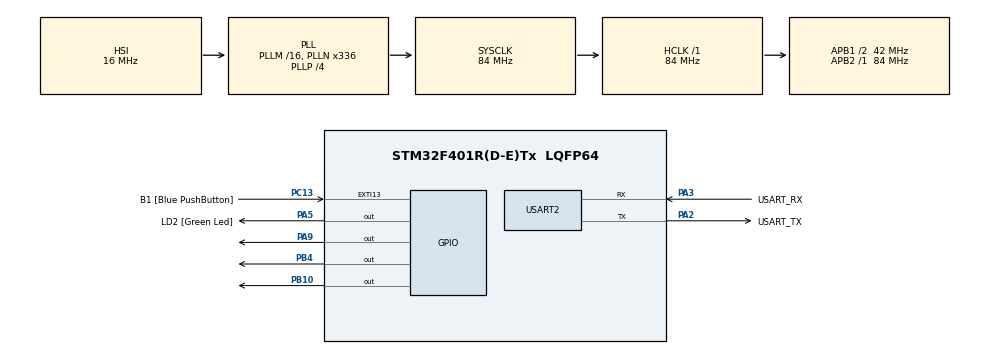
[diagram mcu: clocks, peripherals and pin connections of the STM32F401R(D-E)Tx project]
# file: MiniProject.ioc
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Mcu.Family=STM32F4
Mcu.Name=STM32F401R(D-E)Tx
Mcu.Package=LQFP64
NVIC.PriorityGroup=NVIC_PRIORITYGROUP_4
NVIC.TIM1_BRK_TIM9_IRQn=true\:0\:0\:false\:false\:true\:false\:true\:true
NVIC.TimeBase=TIM1_BRK_TIM9_IRQn
NVIC.TimeBaseIP=TIM9
NVIC.USART2_IRQn=true\:6\:0\:true\:false\:true\:true\:true\:true
PA13.GPIO_Label=TMS
PA13.Signal=SYS_JTMS-SWDIO
PA14.GPIO_Label=TCK
PA14.Signal=SYS_JTCK-SWCLK
PA2.GPIO_Label=USART_TX
PA2.GPIO_Mode=GPIO_MODE_AF_PP
PA2.GPIO_PuPd=GPIO_NOPULL
PA2.GPIO_Speed=GPIO_SPEED_FREQ_LOW
PA2.Mode=Asynchronous
PA2.Signal=USART2_TX
PA3.GPIO_Label=USART_RX
PA3.GPIO_Mode=GPIO_MODE_AF_PP
PA3.GPIO_PuPd=GPIO_NOPULL
PA3.GPIO_Speed=GPIO_SPEED_FREQ_LOW
PA3.Mode=Asynchronous
PA3.Signal=USART2_RX
PA5.GPIO_Label=LD2 [Green Led]
PA5.GPIO_Mode=GPIO_MODE_OUTPUT_PP
PA5.GPIO_PuPd=GPIO_NOPULL
PA5.GPIO_Speed=GPIO_SPEED_FREQ_LOW
PA5.Signal=GPIO_Output
PA9.Signal=GPIO_Output
PB10.Signal=GPIO_Output
PB3.GPIO_Label=SWO
PB3.Signal=SYS_JTDO-SWO
PB4.Signal=GPIO_Output
PC13-ANTI_TAMP.GPIO_Label=B1 [Blue PushButton]
PC13-ANTI_TAMP.GPIO_ModeDefaultEXTI=GPIO_MODE_IT_FALLING
PC13-ANTI_TAMP.GPIO_PuPd=GPIO_NOPULL
PC13-ANTI_TAMP.Signal=GPXTI13
PC14-OSC32_IN.Signal=RCC_OSC32_IN
PC15-OSC32_OUT.Signal=RCC_OSC32_OUT
PH0\ -\ OSC_IN.Signal=RCC_OSC_IN
PH1\ -\ OSC_OUT.Signal=RCC_OSC_OUT
ProjectManager.HeapSize=0x200
ProjectManager.StackSize=0x400
ProjectManager.TargetToolchain=STM32CubeIDE
RCC.AHBFreq_Value=84000000
RCC.APB1CLKDivider=RCC_HCLK_DIV2
RCC.APB1Freq_Value=42000000
RCC.APB1TimFreq_Value=84000000
RCC.APB2Freq_Value=84000000
RCC.APB2TimFreq_Value=84000000
RCC.CortexFreq_Value=84000000
RCC.HCLKFreq_Value=84000000
RCC.HSE_VALUE=8000000
RCC.HSI_VALUE=16000000
RCC.LSE_VALUE=32768
RCC.PLLN=336
RCC.PLLP=RCC_PLLP_DIV4
RCC.PLLQ=7
RCC.SYSCLKFreq_VALUE=84000000
RCC.SYSCLKSource=RCC_SYSCLKSOURCE_PLLCLK
RCC.VCOOutputFreq_Value=336000000
RTC.HourFormat=RTC_HOURFORMAT_12
USART2.VirtualMode=VM_ASYNC
VP_RTC_VS_RTC_Activate.Mode=RTC_Enabled
VP_SYS_VS_tim9.Mode=TIM9
board=NUCLEO-F401RE

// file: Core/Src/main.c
/* USER CODE BEGIN Header */
/**
  ******************************************************************************
  * @file           : main.c
  * @brief          : Main program body
  ******************************************************************************
  * @attention
  *
  * Copyright (c) 2024 STMicroelectronics.
  * All rights reserved.
  *
  * This software is licensed under terms that can be found in the LICENSE file
  * in the root directory of this software component.
  * If no LICENSE file comes with this software, it is provided AS-IS.
  *
  ******************************************************************************
  */
/* USER CODE END Header */
#include "main.h"

RTC_HandleTypeDef hrtc;

UART_HandleTypeDef huart2;

void SystemClock_Config(void);
static void MX_GPIO_Init(void);
static void MX_RTC_Init(void);
static void MX_USART2_UART_Init(void);

/* USER CODE BEGIN 0 */

TaskHandle_t handle_menuTask;
TaskHandle_t handle_ledTask;
TaskHandle_t handle_rtcTask;
TaskHandle_t handle_printTask;
TaskHandle_t handle_cmdHandlingTask;

QueueHandle_t inputQueue;
QueueHandle_t printQueue;

TimerHandle_t handle_led_timers[4];
TimerHandle_t rtc_timer;

//User data
uint8_t user_data; //RX Buffer for UART

//State Variable
state_t curr_state = MenuState;
/* USER CODE END 0 */

int main(void)
{

  /* USER CODE BEGIN 1 */
	BaseType_t status;
  /* USER CODE END 1 */

  /* MCU Configuration--------------------------------------------------------*/

  /* Reset of all peripherals, Initializes the Flash interface and the Systick. */
  HAL_Init();

  /* Configure the system clock */
  SystemClock_Config();

  /* Initialize all configured peripherals */
  MX_GPIO_Init();
  MX_RTC_Init();
  MX_USART2_UART_Init();
  /* USER CODE BEGIN 2 */

  //Creating Tasks
   status = xTaskCreate(menuTask_Handler, "Menu_Task", 250, NULL ,2, &handle_menuTask);
   configASSERT(status == pdPASS); //if something went wrong with the task creation we will be stuck in a infinite loop

   status = xTaskCreate(ledTask_Handler, "Led-Task", 250, NULL ,2, &handle_ledTask);
   configASSERT(status == pdPASS);

   status = xTaskCreate(RTCTask_Handler, "RTC-Task", 250, NULL ,2, &handle_rtcTask);
   configASSERT(status == pdPASS);

   status = xTaskCreate(printTask_Handler, "Print-Task", 250, NULL ,2, &handle_printTask);
   configASSERT(status == pdPASS);

   status = xTaskCreate(cmdHandlingTask_Handler, "Command-Handling-Task", 250, NULL ,2, &handle_cmdHandlingTask);
   configASSERT(status == pdPASS);

   //Queues Creation
   inputQueue = xQueueCreate( 10, sizeof( char ) );
   configASSERT(inputQueue != NULL);
   printQueue = xQueueCreate( 10, sizeof( size_t ) );
   configASSERT(printQueue != NULL);

   //Create Timers for each LED effect (We have 4 Leds effect so we are creating 4 Timers , they all use the same callback function)
   for(int i = 0; i<4 ; i++)
	   handle_led_timers[i] = xTimerCreate("led_timer",pdMS_TO_TICKS(100),pdTRUE,(void*)(i+1),led_effect_callback);

   rtc_timer = xTimerCreate ("rtc_report_timer",pdMS_TO_TICKS(1000),pdTRUE,NULL,rtc_report_callback);   // We are using this Timer to display the time every second on ITM

   //Trigger the UART Reception
   HAL_UART_Receive_IT(&huart2, &user_data, 1);
   //Start FreeRTOS Scheduler
   vTaskStartScheduler();
  /* USER CODE END 2 */

  /* Infinite loop */
  while (1)
  {

  }
}

void SystemClock_Config(void)
{
  RCC_OscInitTypeDef RCC_OscInitStruct = {0};
  RCC_ClkInitTypeDef RCC_ClkInitStruct = {0};

  /** Configure the main internal regulator output voltage
  */
  __HAL_RCC_PWR_CLK_ENABLE();
  __HAL_PWR_VOLTAGESCALING_CONFIG(PWR_REGULATOR_VOLTAGE_SCALE2);

  /** Initializes the RCC Oscillators according to the specified parameters
  * in the RCC_OscInitTypeDef structure.
  */
  RCC_OscInitStruct.OscillatorType = RCC_OSCILLATORTYPE_HSI|RCC_OSCILLATORTYPE_LSI;
  RCC_OscInitStruct.HSIState = RCC_HSI_ON;
  RCC_OscInitStruct.HSICalibrationValue = RCC_HSICALIBRATION_DEFAULT;
  RCC_OscInitStruct.LSIState = RCC_LSI_ON;
  RCC_OscInitStruct.PLL.PLLState = RCC_PLL_ON;
  RCC_OscInitStruct.PLL.PLLSource = RCC_PLLSOURCE_HSI;
  RCC_OscInitStruct.PLL.PLLM = 16;
  RCC_OscInitStruct.PLL.PLLN = 336;
  RCC_OscInitStruct.PLL.PLLP = RCC_PLLP_DIV4;
  RCC_OscInitStruct.PLL.PLLQ = 7;
  if (HAL_RCC_OscConfig(&RCC_OscInitStruct) != HAL_OK)
  {
    Error_Handler();
  }

  /** Initializes the CPU, AHB and APB buses clocks
  */
  RCC_ClkInitStruct.ClockType = RCC_CLOCKTYPE_HCLK|RCC_CLOCKTYPE_SYSCLK
                              |RCC_CLOCKTYPE_PCLK1|RCC_CLOCKTYPE_PCLK2;
  RCC_ClkInitStruct.SYSCLKSource = RCC_SYSCLKSOURCE_PLLCLK;
  RCC_ClkInitStruct.AHBCLKDivider = RCC_SYSCLK_DIV1;
  RCC_ClkInitStruct.APB1CLKDivider = RCC_HCLK_DIV2;
  RCC_ClkInitStruct.APB2CLKDivider = RCC_HCLK_DIV1;

  if (HAL_RCC_ClockConfig(&RCC_ClkInitStruct, FLASH_LATENCY_2) != HAL_OK)
  {
    Error_Handler();
  }
}

static void MX_RTC_Init(void)
{

  /** Initialize RTC Only
  */
  hrtc.Instance = RTC;
  hrtc.Init.HourFormat = RTC_HOURFORMAT_12;
  hrtc.Init.AsynchPrediv = 127;
  hrtc.Init.SynchPrediv = 255;
  hrtc.Init.OutPut = RTC_OUTPUT_DISABLE;
  hrtc.Init.OutPutPolarity = RTC_OUTPUT_POLARITY_HIGH;
  hrtc.Init.OutPutType = RTC_OUTPUT_TYPE_OPENDRAIN;
  if (HAL_RTC_Init(&hrtc) != HAL_OK)
  {
    Error_Handler();
  }

}

static void MX_USART2_UART_Init(void)
{

  huart2.Instance = USART2;
  huart2.Init.BaudRate = 115200;
  huart2.Init.WordLength = UART_WORDLENGTH_8B;
  huart2.Init.StopBits = UART_STOPBITS_1;
  huart2.Init.Parity = UART_PARITY_NONE;
  huart2.Init.Mode = UART_MODE_TX_RX;
  huart2.Init.HwFlowCtl = UART_HWCONTROL_NONE;
  huart2.Init.OverSampling = UART_OVERSAMPLING_16;
  if (HAL_UART_Init(&huart2) != HAL_OK)
  {
    Error_Handler();
  }

}

static void MX_GPIO_Init(void)
{
  GPIO_InitTypeDef GPIO_InitStruct = {0};

  /* GPIO Ports Clock Enable */
  __HAL_RCC_GPIOC_CLK_ENABLE();
  __HAL_RCC_GPIOH_CLK_ENABLE();
  __HAL_RCC_GPIOA_CLK_ENABLE();
  __HAL_RCC_GPIOB_CLK_ENABLE();

  /*Configure GPIO pin Output Level */
  HAL_GPIO_WritePin(GPIOA, LD2_Pin|GPIO_PIN_9, GPIO_PIN_RESET);

  /*Configure GPIO pin Output Level */
  HAL_GPIO_WritePin(GPIOB, GPIO_PIN_10|GPIO_PIN_4, GPIO_PIN_RESET);

  /*Configure GPIO pin : B1_Pin */
  GPIO_InitStruct.Pin = B1_Pin;
  GPIO_InitStruct.Mode = GPIO_MODE_IT_FALLING;
  GPIO_InitStruct.Pull = GPIO_NOPULL;
  HAL_GPIO_Init(B1_GPIO_Port, &GPIO_InitStruct);

  /*Configure GPIO pins : LD2_Pin PA9 */
  GPIO_InitStruct.Pin = LD2_Pin|GPIO_PIN_9;
  GPIO_InitStruct.Mode = GPIO_MODE_OUTPUT_PP;
  GPIO_InitStruct.Pull = GPIO_NOPULL;
  GPIO_InitStruct.Speed = GPIO_SPEED_FREQ_LOW;
  HAL_GPIO_Init(GPIOA, &GPIO_InitStruct);

  /*Configure GPIO pins : PB10 PB4 */
  GPIO_InitStruct.Pin = GPIO_PIN_10|GPIO_PIN_9|GPIO_PIN_8;
  GPIO_InitStruct.Mode = GPIO_MODE_OUTPUT_PP;
  GPIO_InitStruct.Pull = GPIO_NOPULL;
  GPIO_InitStruct.Speed = GPIO_SPEED_FREQ_LOW;
  HAL_GPIO_Init(GPIOB, &GPIO_InitStruct);

}

/* USER CODE BEGIN 4 */

/*
 * The Timers callback function it will be called when the timer is expired ! it will get the ID and depends on the ID will execute it's effect
 */
void led_effect_callback(TimerHandle_t xTimer)
{
	uint32_t id;

	 configASSERT( xTimer ); //Check if the xTimer is NULL

	 id = ( uint32_t ) pvTimerGetTimerID( xTimer );

	 switch(id)
	 {
	 case 1:
		 led_effect1();
		 break;
	 case 2:
		 led_effect2();
		 break;
	 case 3:
		 led_effect3();
		 break;
	 case 4:
		 led_effect4();
	 }
}

/*
 * This is callback function for the RTC timer , it will show the time and date on the ITM (You have to enable it)
 */
void rtc_report_callback( TimerHandle_t xTimer )
{
	 show_time_date_itm();

}

void HAL_UART_RxCpltCallback(UART_HandleTypeDef *huart)
{
/*
 * Once the data is received , this Callback function will be excuted
 * Here we are going to process the received data (a single byte) when we have an UART IT
 */

	if(xQueueIsQueueFullFromISR(inputQueue) != pdTRUE) //If the Q is not full
	{
		xQueueSendFromISR(inputQueue, &user_data, NULL); //we will enqueue the received byte
	}else{
		/*Queue is full */

		if(user_data == '\n') //If the received byte is \n character
		{
			uint8_t dummy ;
			xQueueReceiveFromISR(inputQueue,&dummy,NULL); //We will leave space by deleting a character
			xQueueSendFromISR(inputQueue,&user_data,NULL); // and we will enqueue the \n character
		}
	}
	if(user_data == '\n'){
		xTaskNotifyFromISR(handle_cmdHandlingTask,0,eNoAction,NULL); //Whenever we receive \n character we to notify the Command Handling Task
	}

	//Enable UART Reception once again
	HAL_UART_Receive_IT(&huart2,&user_data, 1); //Setting our UART to receive data through IT
}

/* USER CODE END 4 */

void HAL_TIM_PeriodElapsedCallback(TIM_HandleTypeDef *htim)
{
  if (htim->Instance == TIM9) {
    HAL_IncTick();
  }
}

void Error_Handler(void)
{
  __disable_irq();
  while (1)
  {
  }
}
